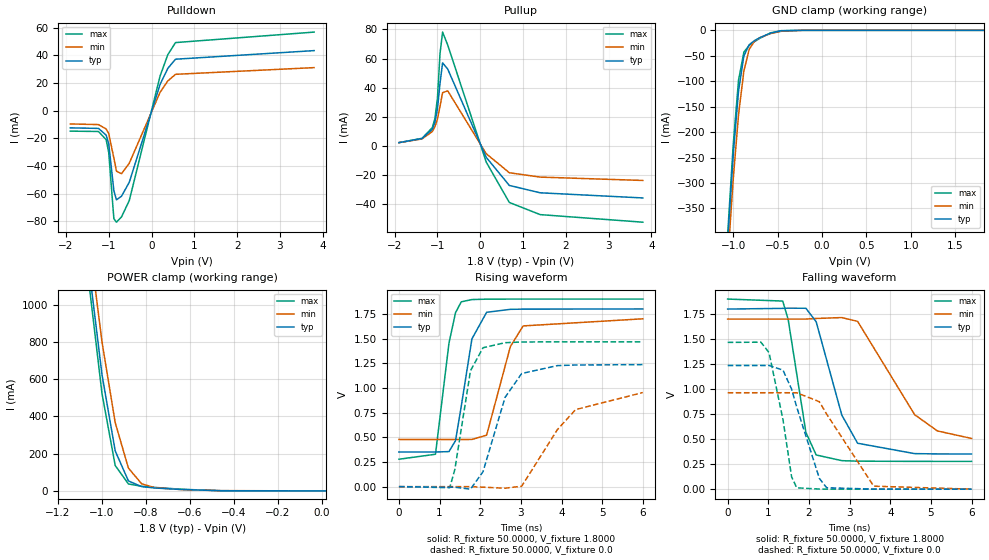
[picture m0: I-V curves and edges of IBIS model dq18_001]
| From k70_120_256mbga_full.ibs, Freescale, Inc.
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|   Model dq18_001
[Model]  dq18_001
Model_type 3-state
Polarity   Non-Inverting
Enable   Active-High
Vmeas =  0.9000V
Cref =   5.0000pF
Rref =   50.0000
C_comp   2.8000pF   2.5000pF   3.3000pF
[Temperature Range]   25.0000   0.1250k   -40.0000
[Voltage Range]   1.8000V   1.7000V   1.9000V
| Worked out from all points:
|   slope of the pulldown table from 0 to 0.27 V, typ, clamps not added: 11.2 ohm
|   slope of the pullup table from 0 to 0.27 V, typ, clamps not added: 18.8 ohm
|   GND clamp passes 1 mA (typ) near -0.46 V on its own axis
|   POWER clamp passes 1 mA (typ) near -0.45 V on its own axis
|   rising waveform, R_fixture 50.0000, V_fixture 1.8000: 20-80 % time 330ps typ, 428ps min, 275ps max; typ from 0.351 V to 1.8 V
|   rising waveform, R_fixture 50.0000, V_fixture 0.0: 20-80 % time 568ps typ, 924ps min, 338ps max; typ from 0 V to 1.24 V
|   falling waveform, R_fixture 50.0000, V_fixture 1.8000: 20-80 % time 609ps typ, 1.01ns min, 369ps max; typ from 1.8 V to 0.351 V
|   falling waveform, R_fixture 50.0000, V_fixture 0.0: 20-80 % time 564ps typ, 819ps min, 364ps max; typ from 1.24 V to 0 V
[Pulldown]
|Voltage   I(typ)   I(min)   I(max)
-1.9V     -12.48mA   -9.645mA   -14.85mA
-1.24V    -12.87mA   -10.11mA   -15.1mA
-1.06V    -17.71mA   -13.28mA   -21.04mA
-1V       -24.03mA   -16.63mA   -30.34mA
-880mV    -57.93mA   -34.36mA   -78.22mA
-820mV    -64.53mA   -43.78mA   -80.71mA
-700mV    -61.88mA   -45.64mA   -76.82mA
-520mV    -51.83mA   -38.06mA   -65.05mA
200mV     18.96mA    13.28mA    25.03mA
380mV     30.52mA    21.42mA    40.4mA
560mV     37.18mA    26.25mA    49.21mA
3.8V      43.4mA     31.1mA     56.8mA
[Pullup]
|Voltage   I(typ)   I(min)   I(max)
-1.9V     2.1mA      2.1mA      2.1mA
-1.36V    4.93mA     4.65mA     5.08mA
-1.12V    11.29mA    9.74mA     12.41mA
-1.06V    15.99mA    12.93mA    18.53mA
-1V       25.26mA    18.31mA    32.65mA
-940mV    42.87mA    27.06mA    63.32mA
-880mV    57.01mA    36.48mA    78.2mA
-760mV    52.75mA    37.76mA    69.31mA
140mV     -8.031mA   -5.52mA    -11.29mA
680mV     -27.37mA   -18.62mA   -39.09mA
1.4V      -32.43mA   -21.63mA   -47.45mA
3.8V      -35.98mA   -23.94mA   -52.67mA
[GND_clamp]
|Voltage   I(typ)   I(min)   I(max)
-1.9V     -3.325A    -3.292A    -3.363A
-1.06V    -406.3mA   -447.1mA   -394.3mA
-1V       -244.8mA   -292.7mA   -225.2mA
-940mV    -119.2mA   -165.9mA   -97.93mA
-880mV    -50.27mA   -79.72mA   -42.82mA
-820mV    -28.21mA   -37.11mA   -29.64mA
-760mV    -20.14mA   -21.2mA    -22.19mA
-700mV    -14.39mA   -14.35mA   -15.54mA
-580mV    -5.519mA   -6.442mA   -5.033mA
-460mV    -1.016mA   -1.861mA   -601.4uA
-220mV    -979.5nA   -15.35uA   -59.46nA
1.82V     915.2pA    951.9nA    210.6pA
[POWER_clamp]
|Voltage   I(typ)   I(min)   I(max)
-1.9V     11.94A     11.89A     12.02A
-1.06V    1.204A     1.363A     1.122A
-1V       623.7mA    800mA      522.5mA
-940mV    215.1mA    367.1mA    136.6mA
-880mV    53.67mA    122.9mA    37.6mA
-820mV    23.13mA    38.48mA    24.96mA
-760mV    15.75mA    17.21mA    18.82mA
-640mV    7.758mA    7.284mA    9.105mA
-460mV    1.139mA    1.585mA    966.7uA
20mV      398.7pA    26.73nA    225pA
[Ramp]
| variable   typ   min   max
dV/dt_r  0.7414/0.5685n   0.5719/0.9239n   0.8802/0.3375n
dV/dt_f  0.8693/0.6089n   0.7159/1.0075n   0.9734/0.3690n
R_load = 50.0000
[Rising Waveform]
R_fixture= 50.0000
V_fixture= 1.8000
V_fixture_min= 1.7000
V_fixture_max= 1.9000
|time   V(typ)   V(min)   V(max)
0s        350.9mV    477.7mV    277.6mV
899.1ps   350.9mV    477.7mV    328mV
1.231ns   354.9mV    477.7mV    1.454V
1.392ns   465.8mV    477.7mV    1.762V
1.533ns   813.5mV    477.7mV    1.872V
1.795ns   1.496V     478mV      1.895V
2.157ns   1.766V     521.3mV    1.899V
2.742ns   1.796V     1.42V      1.9V
3.056ns   1.798V     1.628V     1.9V
6ns       1.8V       1.7V       1.9V
[Rising Waveform]
R_fixture= 50.0000
V_fixture= 0.0
|time   V(typ)   V(min)   V(max)
0s        4.833nV    524nV      1.315nV
1.25ns    -6.015mV   922.5nV    -10.52mV
1.375ns   -6.053mV   486.9nV    173.4mV
1.76ns    -25.65mV   123.9uV    1.174V
2.069ns   151.8mV    -5.605mV   1.407V
2.611ns   904.4mV    -15.77mV   1.458V
3.02ns    1.146V     4.313mV    1.465V
3.9ns     1.226V     579.1mV    1.467V
4.346ns   1.232V     780.3mV    1.467V
6ns       1.236V     953.1mV    1.467V
[Falling Waveform]
R_fixture= 50.0000
V_fixture= 1.8000
V_fixture_min= 1.7000
V_fixture_max= 1.9000
|time   V(typ)   V(min)   V(max)
0s        1.8V       1.7V       1.9V
1.355ns   1.807V     1.7V       1.88V
1.49ns    1.809V     1.7V       1.694V
1.925ns   1.808V     1.7V       567.5mV
2.178ns   1.673V     1.706V     341.7mV
2.809ns   739.5mV    1.715V     284.9mV
3.197ns   459mV      1.677V     279.8mV
4.601ns   355.2mV    744mV      277.7mV
5.161ns   352.3mV    582mV      277.6mV
6ns       351.2mV    506.9mV    277.6mV
[Falling Waveform]
R_fixture= 50.0000
V_fixture= 0.0
|time   V(typ)   V(min)   V(max)
0s        1.236V     963.7mV    1.467V
818.3ps   1.236V     963.7mV    1.469V
1.018ns   1.236V     963.7mV    1.365V
1.361ns   1.19V      963.7mV    695.4mV
1.574ns   999mV      963.7mV    121.9mV
1.7ns     819.3mV    963.6mV    13.66mV
2.256ns   107.8mV    874mV      866.3uV
2.435ns   14.34mV    750.4mV    492.2uV
3.593ns   351.8uV    29.78mV    13.51uV
6ns       1.794uV    125.3uV    192nV
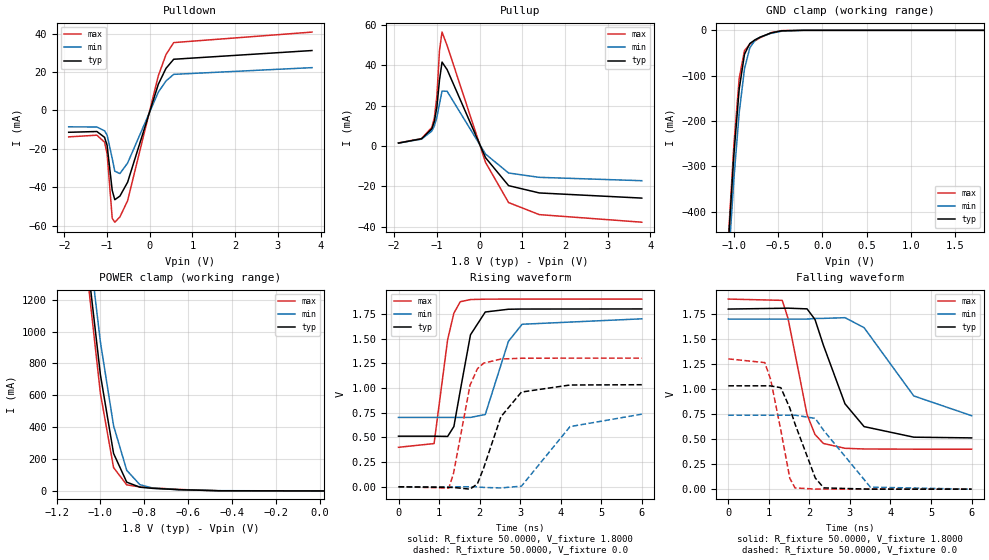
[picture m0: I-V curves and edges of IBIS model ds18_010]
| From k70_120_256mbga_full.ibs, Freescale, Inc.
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|   Model ds18_010
[Model]  ds18_010
Model_type 3-state
Polarity   Non-Inverting
Enable   Active-High
Vmeas =  0.9000V
Cref =   5.0000pF
Rref =   50.0000
C_comp   2.8000pF   2.5000pF   3.3000pF
[Temperature Range]   25.0000   0.1250k   -40.0000
[Voltage Range]   1.8000V   1.7000V   1.9000V
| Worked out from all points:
|   slope of the pulldown table from 0 to 0.27 V, typ, clamps not added: 15.6 ohm
|   slope of the pullup table from 0 to 0.27 V, typ, clamps not added: 26.3 ohm
|   GND clamp passes 1 mA (typ) near -0.46 V on its own axis
|   POWER clamp passes 1 mA (typ) near -0.45 V on its own axis
|   rising waveform, R_fixture 50.0000, V_fixture 1.8000: 20-80 % time 332ps typ, 420ps min, 279ps max; typ from 0.512 V to 1.8 V
|   rising waveform, R_fixture 50.0000, V_fixture 0.0: 20-80 % time 576ps typ, 829ps min, 362ps max; typ from 0 V to 1.03 V
|   falling waveform, R_fixture 50.0000, V_fixture 1.8000: 20-80 % time 735ps typ, 1.06ns min, 456ps max; typ from 1.8 V to 0.512 V
|   falling waveform, R_fixture 50.0000, V_fixture 0.0: 20-80 % time 548ps typ, 770ps min, 370ps max; typ from 1.03 V to 0 V
[Pulldown]
|Voltage   I(typ)   I(min)   I(max)
-1.9V     -11.35mA   -8.503mA   -13.74mA
-1.24V    -10.95mA   -8.605mA   -12.86mA
-1.06V    -13.95mA   -10.57mA   -16.48mA
-1V       -18.14mA   -12.8mA    -22.49mA
-880mV    -41.61mA   -25.01mA   -56.09mA
-820mV    -46.44mA   -31.58mA   -58.14mA
-700mV    -44.56mA   -32.83mA   -55.4mA
-520mV    -37.35mA   -27.37mA   -46.96mA
200mV     13.65mA    9.544mA    18.08mA
380mV     21.93mA    15.36mA    29.09mA
560mV     26.66mA    18.8mA     35.33mA
3.8V      31.2mA     22.3mA     40.8mA
[Pullup]
|Voltage   I(typ)   I(min)   I(max)
-1.9V     1.5mA      1.5mA      1.6mA
-1.36V    3.65mA     3.47mA     3.72mA
-1.12V    8.53mA     7.45mA     9.25mA
-1.06V    12.22mA    10mA       13.99mA
-1V       19.5mA     14.26mA    24.92mA
-940mV    32.64mA    20.94mA    47.33mA
-880mV    41.63mA    27.29mA    56.5mA
-760mV    37.88mA    27.15mA    49.81mA
140mV     -5.754mA   -3.953mA   -8.093mA
680mV     -19.59mA   -13.32mA   -27.98mA
1.4V      -23.2mA    -15.47mA   -33.94mA
3.8V      -25.75mA   -17.13mA   -37.69mA
[GND_clamp]
|Voltage   I(typ)   I(min)   I(max)
-1.9V     -3.878A    -3.837A    -3.923A
-1.06V    -463.8mA   -508.7mA   -451.5mA
-1V       -275.2mA   -328.6mA   -253.7mA
-940mV    -129.8mA   -182.1mA   -106.1mA
-880mV    -52.66mA   -84.81mA   -44.51mA
-820mV    -29.1mA    -38.53mA   -30.59mA
-760mV    -20.73mA   -21.81mA   -22.88mA
-700mV    -14.8mA    -14.73mA   -16.01mA
-580mV    -5.66mA    -6.597mA   -5.171mA
-460mV    -1.037mA   -1.9mA     -614.7uA
-220mV    -1.001uA   -15.63uA   -61.01nA
1.82V     927pA      961.6nA    217.2pA
[POWER_clamp]
|Voltage   I(typ)   I(min)   I(max)
-1.9V     14.99A     14.89A     15.1A
-1.06V    1.452A     1.634A     1.361A
-1V       729.6mA    935mA      612.3mA
-940mV    235.7mA    409.7mA    146.8mA
-880mV    55.12mA    129.3mA    38.22mA
-820mV    23.43mA    39.21mA    25.26mA
-760mV    15.93mA    17.42mA    19.04mA
-640mV    7.842mA    7.361mA    9.207mA
-460mV    1.151mA    1.601mA    977.3uA
20mV      403.6pA    26.53nA    232.4pA
[Ramp]
| variable   typ   min   max
dV/dt_r  0.6197/0.5761n   0.4409/0.8291n   0.7813/0.3624n
dV/dt_f  0.7726/0.7350n   0.5794/1.0619n   0.9002/0.4562n
R_load = 50.0000
[Rising Waveform]
R_fixture= 50.0000
V_fixture= 1.8000
V_fixture_min= 1.7000
V_fixture_max= 1.9000
|time   V(typ)   V(min)   V(max)
0s        512mV      701.7mV    399.6mV
877.1ps   512mV      701.7mV    437.2mV
1.212ns   509.6mV    701.7mV    1.49V
1.366ns   609.7mV    701.7mV    1.757V
1.523ns   972.3mV    701.7mV    1.873V
1.775ns   1.538V     702mV      1.895V
2.14ns    1.769V     731.4mV    1.899V
2.711ns   1.797V     1.472V     1.9V
3.048ns   1.799V     1.645V     1.9V
6ns       1.8V       1.7V       1.9V
[Rising Waveform]
R_fixture= 50.0000
V_fixture= 0.0
|time   V(typ)   V(min)   V(max)
0s        6.543nV    688.4nV    1.841nV
1.241ns   -6.341mV   1.125uV    -12.99mV
1.357ns   -6.979mV   754.1nV    135.7mV
1.764ns   -24.27mV   120.2uV    1.028V
1.947ns   30.13mV    -796.8uV   1.195V
2.1ns     189.5mV    -6.877mV   1.251V
2.525ns   708.3mV    -11.98mV   1.293V
3.033ns   958.8mV    6.379mV    1.301V
4.229ns   1.03V      608.7mV    1.302V
6ns       1.033V     734.8mV    1.302V
[Falling Waveform]
R_fixture= 50.0000
V_fixture= 1.8000
V_fixture_min= 1.7000
V_fixture_max= 1.9000
|time   V(typ)   V(min)   V(max)
0s        1.8V       1.7V       1.9V
1.33ns    1.808V     1.7V       1.887V
1.471ns   1.809V     1.7V       1.711V
1.942ns   1.802V     1.7V       746.2mV
2.138ns   1.696V     1.706V     546.7mV
2.345ns   1.439V     1.707V     456.8mV
2.878ns   853mV      1.714V     408.5mV
3.349ns   625.2mV    1.614V     401.6mV
4.574ns   519.6mV    931.8mV    399.7mV
6ns       512.4mV    734.4mV    399.6mV
[Falling Waveform]
R_fixture= 50.0000
V_fixture= 0.0
|time   V(typ)   V(min)   V(max)
0s        1.033V     739.5mV    1.302V
899.6ps   1.033V     739.5mV    1.265V
1.046ns   1.032V     739.5mV    1.095V
1.296ns   1.014V     739.5mV    587.7mV
1.517ns   810.4mV    739.5mV    108.6mV
1.646ns   650.5mV    739.4mV    12.53mV
2.145ns   111.9mV    707.5mV    885.8uV
2.354ns   12.76mV    585.7mV    434.6uV
3.504ns   280.9uV    20.2mV     12.38uV
6ns       1.725uV    73.49uV    177.7nV
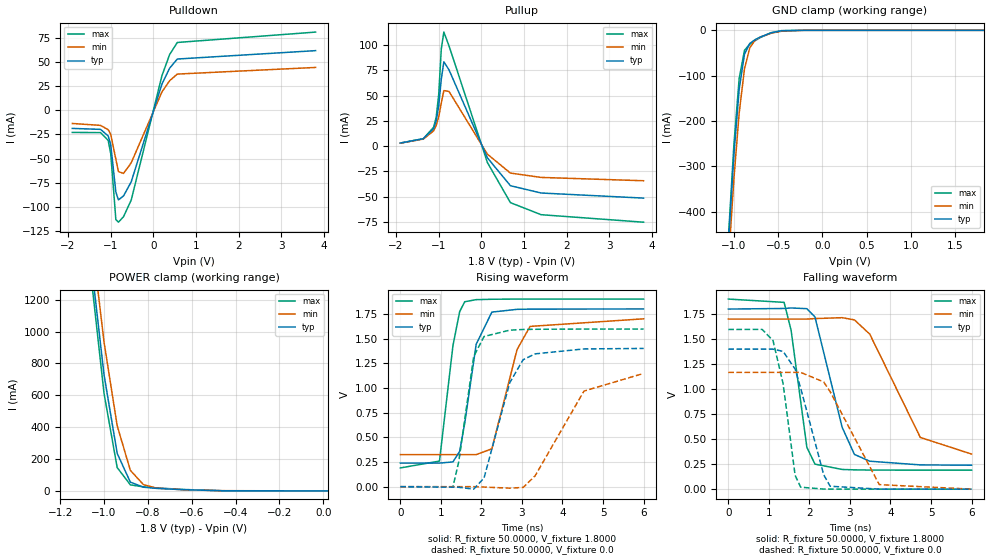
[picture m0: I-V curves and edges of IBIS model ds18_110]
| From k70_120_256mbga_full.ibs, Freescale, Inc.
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|   Model ds18_110
[Model]  ds18_110
Model_type 3-state
Polarity   Non-Inverting
Enable   Active-High
Vmeas =  0.9000V
Cref =   5.0000pF
Rref =   50.0000
C_comp   2.8000pF   2.5000pF   3.3000pF
[Temperature Range]   25.0000   0.1250k   -40.0000
[Voltage Range]   1.8000V   1.7000V   1.9000V
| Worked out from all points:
|   slope of the pulldown table from 0 to 0.27 V, typ, clamps not added: 7.88 ohm
|   slope of the pullup table from 0 to 0.27 V, typ, clamps not added: 13.2 ohm
|   GND clamp passes 1 mA (typ) near -0.46 V on its own axis
|   POWER clamp passes 1 mA (typ) near -0.45 V on its own axis
|   rising waveform, R_fixture 50.0000, V_fixture 1.8000: 20-80 % time 343ps typ, 452ps min, 280ps max; typ from 0.239 V to 1.8 V
|   rising waveform, R_fixture 50.0000, V_fixture 0.0: 20-80 % time 551ps typ, 931ps min, 325ps max; typ from 0 V to 1.4 V
|   falling waveform, R_fixture 50.0000, V_fixture 1.8000: 20-80 % time 531ps typ, 901ps min, 329ps max; typ from 1.8 V to 0.239 V
|   falling waveform, R_fixture 50.0000, V_fixture 0.0: 20-80 % time 560ps typ, 838ps min, 337ps max; typ from 1.4 V to 0 V
[Pulldown]
|Voltage   I(typ)   I(min)   I(max)
-1.9V     -18.81mA   -13.71mA   -22.98mA
-1.24V    -19.81mA   -15.67mA   -23.14mA
-1.06V    -26.52mA   -20.1mA    -31.21mA
-1V       -35.76mA   -24.94mA   -44.82mA
-880mV    -84.6mA    -50.72mA   -113.1mA
-820mV    -92.83mA   -63.56mA   -115.9mA
-700mV    -88.69mA   -65.42mA   -110.2mA
-520mV    -74.14mA   -54.44mA   -93.04mA
200mV     27.05mA    18.96mA    35.72mA
380mV     43.53mA    30.56mA    57.62mA
560mV     53.01mA    37.44mA    70.15mA
3.8V      61.7mA     44.3mA     80.9mA
[Pullup]
|Voltage   I(typ)   I(min)   I(max)
-1.9V     3.1mA      3mA        3.1mA
-1.36V    7.36mA     7.03mA     7.49mA
-1.12V    17.36mA    15.18mA    18.79mA
-1.06V    24.97mA    20.43mA    28.57mA
-1V       39.98mA    29.19mA    51.25mA
-940mV    66.5mA     42.69mA    96.33mA
-880mV    83.54mA    55.03mA    113mA
-760mV    75.68mA    54.28mA    99.49mA
140mV     -11.5mA    -7.9mA     -16.16mA
680mV     -39.16mA   -26.64mA   -55.92mA
1.4V      -46.38mA   -30.94mA   -67.86mA
3.8V      -51.43mA   -34.23mA   -75.28mA
[GND_clamp]
|Voltage   I(typ)   I(min)   I(max)
-1.9V     -3.876A    -3.836A    -3.92A
-1.06V    -463.3mA   -508.2mA   -450.9mA
-1V       -274.7mA   -328.2mA   -253.2mA
-940mV    -129.5mA   -181.7mA   -105.7mA
-880mV    -52.3mA    -84.51mA   -44.05mA
-820mV    -28.81mA   -38.3mA    -30.21mA
-760mV    -20.5mA    -21.64mA   -22.59mA
-700mV    -14.65mA   -14.61mA   -15.81mA
-580mV    -5.613mA   -6.549mA   -5.122mA
-460mV    -1.034mA   -1.892mA   -613.3uA
-220mV    -1.001uA   -15.63uA   -61.01nA
1.82V     927pA      961.6nA    217.2pA
[POWER_clamp]
|Voltage   I(typ)   I(min)   I(max)
-1.9V     14.99A     14.89A     15.1A
-1.06V    1.452A     1.634A     1.361A
-1V       729.6mA    935mA      612.3mA
-940mV    235.7mA    409.7mA    146.8mA
-880mV    55.12mA    129.3mA    38.22mA
-820mV    23.43mA    39.21mA    25.26mA
-760mV    15.93mA    17.42mA    19.04mA
-640mV    7.842mA    7.361mA    9.207mA
-460mV    1.151mA    1.601mA    977.3uA
20mV      403.6pA    26.53nA    232.4pA
[Ramp]
| variable   typ   min   max
dV/dt_r  0.8399/0.5514n   0.6880/0.9308n   0.9576/0.3245n
dV/dt_f  0.9364/0.5311n   0.8096/0.9007n   1.0261/0.3286n
R_load = 50.0000
[Rising Waveform]
R_fixture= 50.0000
V_fixture= 1.8000
V_fixture_min= 1.7000
V_fixture_max= 1.9000
|time   V(typ)   V(min)   V(max)
0s        239mV      324.7mV    189.8mV
966ps     239mV      324.7mV    259.4mV
1.298ns   250.7mV    324.7mV    1.428V
1.464ns   358mV      324.7mV    1.773V
1.588ns   640.5mV    324.7mV    1.873V
1.871ns   1.442V     324.8mV    1.894V
2.258ns   1.768V     383.3mV    1.898V
2.879ns   1.796V     1.388V     1.9V
3.199ns   1.798V     1.623V     1.9V
6ns       1.8V       1.7V       1.9V
[Rising Waveform]
R_fixture= 50.0000
V_fixture= 0.0
|time   V(typ)   V(min)   V(max)
0s        3.712nV    402.4nV    1.028nV
1.298ns   -4.924mV   597.9nV    -965.7uV
1.441ns   -5.965mV   -720.9nV   252.6mV
1.809ns   -25.21mV   177.7uV    1.318V
2.066ns   88.99mV    -3.903mV   1.521V
2.698ns   1.052V     -15.05mV   1.585V
3.029ns   1.286V     -7.859mV   1.592V
3.323ns   1.345V     108.5mV    1.594V
4.529ns   1.395V     968.2mV    1.596V
6ns       1.4V       1.147V     1.596V
[Falling Waveform]
R_fixture= 50.0000
V_fixture= 1.8000
V_fixture_min= 1.7000
V_fixture_max= 1.9000
|time   V(typ)   V(min)   V(max)
0s        1.8V       1.7V       1.9V
1.376ns   1.806V     1.7V       1.867V
1.548ns   1.811V     1.7V       1.589V
1.937ns   1.804V     1.7V       418.8mV
2.137ns   1.721V     1.705V     250.4mV
2.807ns   619.1mV    1.714V     197mV
3.11ns    347.5mV    1.692V     193mV
3.488ns   279.4mV    1.55V      191mV
4.735ns   242.5mV    517.2mV    189.8mV
6ns       239.3mV    350.7mV    189.8mV
[Falling Waveform]
R_fixture= 50.0000
V_fixture= 0.0
|time   V(typ)   V(min)   V(max)
0s        1.4V       1.167V     1.596V
832.3ps   1.4V       1.167V     1.597V
1.102ns   1.4V       1.167V     1.486V
1.351ns   1.377V     1.167V     1.055V
1.648ns   1.2V       1.167V     137.6mV
1.785ns   1.009V     1.167V     19.76mV
2.351ns   145.4mV    1.072V     979.1uV
2.511ns   29.22mV    975.6mV    637.1uV
3.723ns   453.4uV    45.31mV    22.21uV
6ns       4.926uV    235.9uV    -115nV
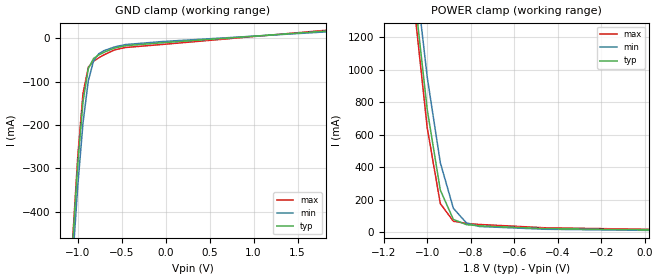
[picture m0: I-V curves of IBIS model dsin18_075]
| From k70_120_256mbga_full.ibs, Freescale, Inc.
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|   Model dsin18_075
[Model]  dsin18_075
Model_type Input
Polarity   Non-Inverting
Enable   Active-High
Vinl =   0.6500V
Vinh =   1.1500V
C_comp   2.8000pF   2.5000pF   3.3000pF
[Temperature Range]   25.0000   0.1250k   -40.0000
[Voltage Range]   1.8000V   1.7000V   1.9000V
[GND_clamp]
|Voltage   I(typ)   I(min)   I(max)
-1.9V     -3.899A    -3.854A    -3.95A
-1.06V    -479.8mA   -521.6mA   -471.7mA
-1V       -291.3mA   -341.4mA   -274.1mA
-940mV    -146.6mA   -195.2mA   -127.5mA
-880mV    -70.23mA   -98.41mA   -66.94mA
-820mV    -46.95mA   -52.52mA   -53.09mA
-760mV    -38.48mA   -35.87mA   -45.23mA
-700mV    -32.4mA    -28.69mA   -38.2mA
-580mV    -22.84mA   -20.17mA   -26.97mA
-460mV    -17.47mA   -14.86mA   -21.56mA
-40mV     -10.61mA   -7.836mA   -14.54mA
1.82V     16.27mA    14.37mA    18.11mA
[POWER_clamp]
|Voltage   I(typ)   I(min)   I(max)
-1.9V     15A        14.9A      15.12A
-1.06V    1.475A     1.651A     1.39A
-1V       753.4mA    953mA      641.7mA
-940mV    260.1mA    428.2mA    177.2mA
-880mV    79.86mA    148.3mA    68.7mA
-820mV    48.09mA    58.36mA    55.54mA
-760mV    40.42mA    36.59mA    49.06mA
-460mV    23.77mA    19.64mA    28.67mA
20mV      15.66mA    12.62mA    19.22mA
